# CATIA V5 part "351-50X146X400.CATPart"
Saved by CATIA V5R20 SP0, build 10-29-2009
Part number: 351-50X146X400
Definition: NONE
Nomenclature: 351-50X146X400
Source: Unknown
Description: 351-50X146X400
Bounding box of the stored display mesh (mm): x -10 to 390, y -32.5 to 32.5, z -32.5 to 32.5
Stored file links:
  C:\Users\Utente\Desktop\IO LAVORO\3D X SITO CF\X SITO\PLASTICA\351\351-50X146X400.CATPart

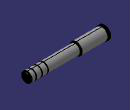
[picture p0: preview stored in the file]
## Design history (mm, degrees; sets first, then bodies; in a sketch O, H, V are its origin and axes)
Body1 "351-50X146X400" (main body)
  Solid1: solid without history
